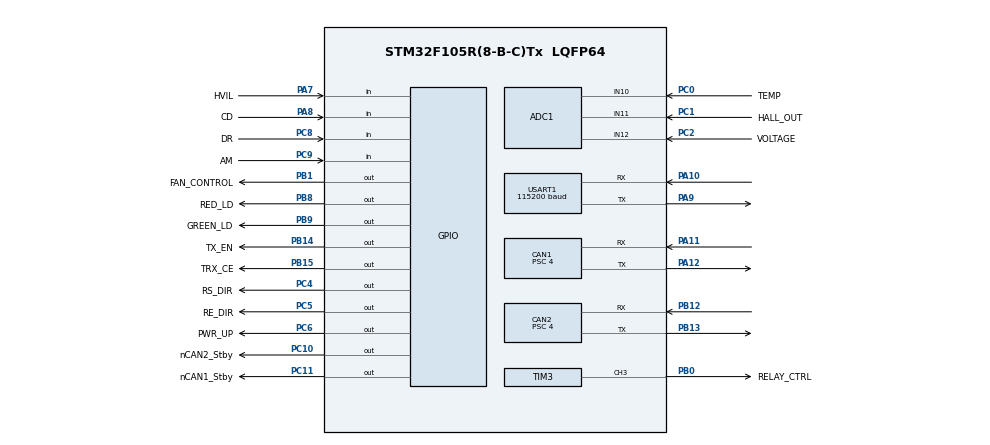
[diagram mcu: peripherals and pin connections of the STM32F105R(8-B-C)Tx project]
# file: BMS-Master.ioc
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ADC1.Channel-0\#ChannelRegularConversion=ADC_CHANNEL_10
ADC1.Channel-1\#ChannelRegularConversion=ADC_CHANNEL_11
ADC1.Channel-2\#ChannelRegularConversion=ADC_CHANNEL_12
ADC1.ContinuousConvMode=ENABLE
ADC1.NbrOfConversion=3
ADC1.NbrOfConversionFlag=1
ADC1.Rank-0\#ChannelRegularConversion=1
ADC1.Rank-1\#ChannelRegularConversion=2
ADC1.Rank-2\#ChannelRegularConversion=3
ADC1.SamplingTime-0\#ChannelRegularConversion=ADC_SAMPLETIME_1CYCLE_5
ADC1.SamplingTime-1\#ChannelRegularConversion=ADC_SAMPLETIME_1CYCLE_5
ADC1.SamplingTime-2\#ChannelRegularConversion=ADC_SAMPLETIME_1CYCLE_5
ADC1.master=1
CAN1.BS1=CAN_BS1_13TQ
CAN1.BS2=CAN_BS2_4TQ
CAN1.CalculateBaudRate=500000
CAN1.CalculateTimeBit=2000
CAN1.CalculateTimeQuantum=111.11111111111111
CAN1.Prescaler=4
CAN2.AWUM=ENABLE
CAN2.BS1=CAN_BS1_13TQ
CAN2.BS2=CAN_BS2_4TQ
CAN2.CalculateBaudRate=500000
CAN2.CalculateTimeBit=2000
CAN2.CalculateTimeQuantum=111.11111111111111
CAN2.Prescaler=4
Dma.ADC1.0.Direction=DMA_PERIPH_TO_MEMORY
Dma.ADC1.0.Instance=DMA1_Channel1
Dma.ADC1.0.MemDataAlignment=DMA_MDATAALIGN_HALFWORD
Dma.ADC1.0.MemInc=DMA_MINC_ENABLE
Dma.ADC1.0.Mode=DMA_CIRCULAR
Dma.ADC1.0.PeriphDataAlignment=DMA_PDATAALIGN_HALFWORD
Dma.ADC1.0.PeriphInc=DMA_PINC_DISABLE
Dma.ADC1.0.Priority=DMA_PRIORITY_LOW
Dma.Request0=ADC1
Mcu.Family=STM32F1
Mcu.Name=STM32F105R(8-B-C)Tx
Mcu.Package=LQFP64
NVIC.CAN2_RX0_IRQn=true\:2\:0\:true\:true\:true\:2\:true\:true\:true
NVIC.DMA1_Channel1_IRQn=true\:3\:0\:true\:true\:true\:1\:false\:true\:true
NVIC.PriorityGroup=NVIC_PRIORITYGROUP_4
PA0-WKUP.Mode=SYS_WakeUp0
PA0-WKUP.Signal=SYS_WKUP
PA10.Mode=Asynchronous
PA10.Signal=USART1_RX
PA11.Mode=CAN_Activate
PA11.Signal=CAN1_RX
PA12.Mode=CAN_Activate
PA12.Signal=CAN1_TX
PA13.Mode=Serial_Wire
PA13.Signal=SYS_JTMS-SWDIO
PA14.Mode=Serial_Wire
PA14.Signal=SYS_JTCK-SWCLK
PA7.GPIO_Label=HVIL
PA7.GPIO_PuPd=GPIO_PULLDOWN
PA7.Signal=GPIO_Input
PA8.GPIO_Label=CD
PA8.GPIO_PuPd=GPIO_PULLUP
PA8.Signal=GPIO_Input
PA9.Mode=Asynchronous
PA9.Signal=USART1_TX
PB0.GPIO_Label=RELAY_CTRL
PB0.Signal=S_TIM3_CH3
PB1.GPIO_Label=FAN_CONTROL
PB1.Signal=GPIO_Output
PB12.Mode=CAN_Activate
PB12.Signal=CAN2_RX
PB13.Mode=CAN_Activate
PB13.Signal=CAN2_TX
PB14.GPIO_Label=TX_EN
PB14.Signal=GPIO_Output
PB15.GPIO_Label=TRX_CE
PB15.Signal=GPIO_Output
PB8.GPIO_Label=RED_LD
PB8.Signal=GPIO_Output
PB9.GPIO_Label=GREEN_LD
PB9.Signal=GPIO_Output
PC0.GPIO_Label=TEMP
PC0.Signal=ADCx_IN10
PC1.GPIO_Label=HALL_OUT
PC1.Signal=ADCx_IN11
PC10.GPIO_Label=nCAN2_Stby
PC10.GPIO_PuPd=GPIO_PULLDOWN
PC10.Signal=GPIO_Output
PC11.GPIO_Label=nCAN1_Stby
PC11.Signal=GPIO_Output
PC2.GPIO_Label=VOLTAGE
PC2.Signal=ADCx_IN12
PC4.GPIO_Label=RS_DIR
PC4.GPIO_PuPd=GPIO_PULLDOWN
PC4.GPIO_Speed=GPIO_SPEED_FREQ_HIGH
PC4.Signal=GPIO_Output
PC5.GPIO_Label=RE_DIR
PC5.GPIO_PuPd=GPIO_PULLDOWN
PC5.Signal=GPIO_Output
PC6.GPIO_Label=PWR_UP
PC6.Signal=GPIO_Output
PC8.GPIO_Label=DR
PC8.GPIO_PuPd=GPIO_PULLUP
PC8.Signal=GPIO_Input
PC9.GPIO_Label=AM
PC9.GPIO_PuPd=GPIO_PULLUP
PC9.Signal=GPIO_Input
PD0-OSC_IN.Signal=RCC_OSC_IN
ProjectManager.HeapSize=0x200
ProjectManager.StackSize=0x400
ProjectManager.TargetToolchain=STM32CubeIDE
RCC.ADCPresc=RCC_ADCPCLK2_DIV8
RCC.AHBFreq_Value=72000000
RCC.APB1CLKDivider=RCC_HCLK_DIV2
RCC.APB1Freq_Value=36000000
RCC.APB1TimFreq_Value=72000000
RCC.APB2CLKDivider=RCC_HCLK_DIV1
RCC.APB2Freq_Value=72000000
RCC.APB2TimFreq_Value=72000000
RCC.HCLKFreq_Value=72000000
RCC.HSEDivPLL=RCC_HSE_PREDIV_DIV2
RCC.HSE_Timout=1000
RCC.HSE_VALUE=16000000
RCC.LSE_VALUE=32.77
RCC.PLLMUL=RCC_PLL_MUL9
RCC.PLLSourceVirtual=RCC_PLLSOURCE_HSE
RCC.SYSCLKFreq_VALUE=72000000
RCC.SYSCLKSource=RCC_SYSCLKSOURCE_PLLCLK
RCC.USBFreq_Value=48000000
SH.ADCx_IN10.0=ADC1_IN10,IN10
SH.ADCx_IN11.0=ADC1_IN11,IN11
SH.ADCx_IN12.0=ADC1_IN12,IN12
SH.S_TIM3_CH3.0=TIM3_CH3,Output Compare3 CH3
TIM3.Channel-Output\ Compare3\ CH3=TIM_CHANNEL_3
TIM3.Period=999
TIM3.Prescaler=71
USART1.BaudRate=115200
USART1.VirtualMode=VM_ASYNC
board=custom

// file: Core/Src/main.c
/* USER CODE BEGIN Header */
/**
  ******************************************************************************
  * @file           : main.c
  * @brief          : Main program body
  ******************************************************************************
  * @attention
  *
  * Copyright (c) 2025 STMicroelectronics.
  * All rights reserved.
  *
  * This software is licensed under terms that can be found in the LICENSE file
  * in the root directory of this software component.
  * If no LICENSE file comes with this software, it is provided AS-IS.
  *
  ******************************************************************************
  */
/* USER CODE END Header */
#include "main.h"
#include "adc.h"
#include "can.h"
#include "dma.h"
#include "tim.h"
#include "usart.h"
#include "gpio.h"

/* USER CODE BEGIN Includes */
#include "BMS.h"
#include "BMS_PWM.h"
/* USER CODE END Includes */

/* USER CODE BEGIN PV */
BMS_TypeDef bms;				/*<Init of BMS's object>*/
uint32_t lastTick;				/*<Init ot variable with stores last tick of LED blinking>*/
/* USER CODE END PV */

void SystemClock_Config(void);
static void MX_NVIC_Init(void);

int main(void)
{

  /* MCU Configuration--------------------------------------------------------*/

  /* Reset of all peripherals, Initializes the Flash interface and the Systick. */
  HAL_Init();

  /* Configure the system clock */
  SystemClock_Config();

  /* Initialize all configured peripherals */
  MX_GPIO_Init();
  MX_DMA_Init();
  MX_ADC1_Init();
  MX_CAN1_Init();
  MX_CAN2_Init();
  MX_USART1_UART_Init();
  MX_TIM3_Init();

  /* Initialize interrupts */
  MX_NVIC_Init();
  /* USER CODE BEGIN 2 */

  /*BMS---------------------------------------------------------*/
  /* Init BMS object + start CAN/ADC/PWM/EH. On failure enter error mode. */
  if(BMS_Init(&bms, &hcan1, &hadc1, &huart1, &htim3) != HAL_OK){
	  BMS_Mode_Change(&bms, BMS_Error);
  }

  /* USER CODE END 2 */

  /* Infinite loop */
  /* USER CODE BEGIN WHILE */

  // reading current tick of firmware
  lastTick = HAL_GetTick();
  while (1)
  {
	  /* Status LED blink (green = normal, red = error) */
	  BMS_Mode_LEDBlink(&bms);

	  /* JK RS485 always polled (bring-up) — even in BMS_Error */
	  (void)BMS_JK_Normal(&bms.bmsJK);

	  /*
	   * Mode dispatch:
	   *   BMS_NORMAL → ADC / CAN / PWM / HVIL / FAN
	   *   BMS_Error  → stop sensing path, PWM sleep stub
	   */
	  if(bms.status == BMS_NORMAL){
		  if(BMS_Mode_Normal(&bms) != HAL_OK){
			  BMS_Mode_Change(&bms, BMS_Error);
		  }
	  }
	  else{
		  BMS_Mode_Error(&bms);
	  }

    /* USER CODE END WHILE */

  }
}

void SystemClock_Config(void)
{
  RCC_OscInitTypeDef RCC_OscInitStruct = {0};
  RCC_ClkInitTypeDef RCC_ClkInitStruct = {0};
  RCC_PeriphCLKInitTypeDef PeriphClkInit = {0};

  /** Initializes the RCC Oscillators according to the specified parameters
  * in the RCC_OscInitTypeDef structure.
  *
  * Board has no HSE (crystal desoldered) — HSI only.
  * HSI 8 MHz → /2 → PLL×9 = 36 MHz SYSCLK.
  */
  RCC_OscInitStruct.OscillatorType = RCC_OSCILLATORTYPE_HSI;
  RCC_OscInitStruct.HSIState = RCC_HSI_ON;
  RCC_OscInitStruct.HSICalibrationValue = RCC_HSICALIBRATION_DEFAULT;
  RCC_OscInitStruct.Prediv1Source = RCC_PREDIV1_SOURCE_HSE;
  RCC_OscInitStruct.PLL.PLLState = RCC_PLL_ON;
  RCC_OscInitStruct.PLL.PLLSource = RCC_PLLSOURCE_HSI_DIV2;
  RCC_OscInitStruct.PLL.PLLMUL = RCC_PLL_MUL9;
  RCC_OscInitStruct.PLL2.PLL2State = RCC_PLL_NONE;
  if (HAL_RCC_OscConfig(&RCC_OscInitStruct) != HAL_OK)
  {
    Error_Handler();
  }

  /** Initializes the CPU, AHB and APB buses clocks
  *  APB1 /1 → 36 MHz (CAN Prescaler=4 → 500 kbit/s).
  *  APB2 /1 → 36 MHz (USART1 ~115200; no tiny PCLK2).
  */
  RCC_ClkInitStruct.ClockType = RCC_CLOCKTYPE_HCLK|RCC_CLOCKTYPE_SYSCLK
                              |RCC_CLOCKTYPE_PCLK1|RCC_CLOCKTYPE_PCLK2;
  RCC_ClkInitStruct.SYSCLKSource = RCC_SYSCLKSOURCE_PLLCLK;
  RCC_ClkInitStruct.AHBCLKDivider = RCC_SYSCLK_DIV1;
  RCC_ClkInitStruct.APB1CLKDivider = RCC_HCLK_DIV1;
  RCC_ClkInitStruct.APB2CLKDivider = RCC_HCLK_DIV1;

  if (HAL_RCC_ClockConfig(&RCC_ClkInitStruct, FLASH_LATENCY_1) != HAL_OK)
  {
    Error_Handler();
  }
  /* ADC max 14 MHz on F1: PCLK2=36 MHz → /4 = 9 MHz */
  PeriphClkInit.PeriphClockSelection = RCC_PERIPHCLK_ADC;
  PeriphClkInit.AdcClockSelection = RCC_ADCPCLK2_DIV4;
  if (HAL_RCCEx_PeriphCLKConfig(&PeriphClkInit) != HAL_OK)
  {
    Error_Handler();
  }

  /** Configure the Systick interrupt time
  */
  __HAL_RCC_PLLI2S_ENABLE();
}

/**
  * @brief NVIC Configuration.
  * @retval None
  */
static void MX_NVIC_Init(void)
{
  /* DMA1_Channel1_IRQn interrupt configuration */
  HAL_NVIC_SetPriority(DMA1_Channel1_IRQn, 3, 0);
  HAL_NVIC_EnableIRQ(DMA1_Channel1_IRQn);
  /* CAN2_RX0_IRQn interrupt configuration */
  HAL_NVIC_SetPriority(CAN2_RX0_IRQn, 2, 0);
  HAL_NVIC_EnableIRQ(CAN2_RX0_IRQn);
}

void Error_Handler(void)
{
  /* USER CODE BEGIN Error_Handler_Debug */

	uint8_t debugBreakPoint[3] = {0x01,0x02,0x03};

	UNUSED(debugBreakPoint);

  /* User can add his own implementation to report the HAL error return state */

  __disable_irq();
  while (1)
  {

  }
  /* USER CODE END Error_Handler_Debug */
}
